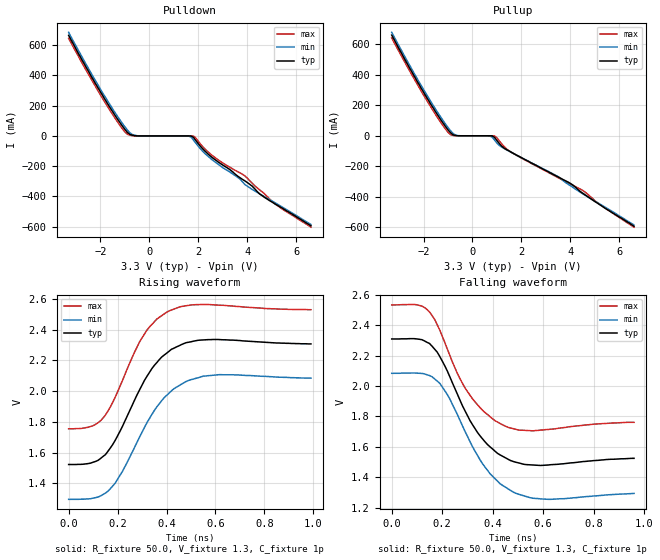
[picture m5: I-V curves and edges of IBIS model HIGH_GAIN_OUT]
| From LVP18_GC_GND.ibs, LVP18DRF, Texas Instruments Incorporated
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|   Driver Output Model
[Model]   HIGH_GAIN_OUT
Model_type   Output_ECL
| Signals   Y,Z
Vmeas = 2.0V   |Reference voltage for timing measurements
Cref = 0pF   |Timing specification test load capacitance value
Rref = 50
|Note: 50 Ohm load; single ended configuration
| variable   typ   min   max
C_comp   0.8pF   0.6pF   0.9pF
|   typ   min   max
[Temperature Range]   25   -40   85
[Voltage range]   3.3V   3.0V   3.6V
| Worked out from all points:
|   rising waveform, R_fixture 50.0, V_fixture 1.3, C_fixture 1p: 20-80 % time 152ps typ, 164ps min, 137ps max; typ from 1.52 V to 2.31 V
|   falling waveform, R_fixture 50.0, V_fixture 1.3, C_fixture 1p: 20-80 % time 142ps typ, 150ps min, 133ps max; typ from 2.31 V to 1.52 V
[Pulldown]
|Voltage I(typ)   I(min)   I(max)
| Note that the[Pulldown]voltage table for (P)ECL is referenced
| to Vcc and is calculated using Vtable=Vcc - Vmeasured.
-3.3V     665mA      685mA      645mA
-1.6V     185mA      204mA      166mA
-1V       43mA       59.7mA     26.4mA
-800mV    10.5mA     21.4mA     5.1mA
-400mV    4.63uA     184uA      6.49nA
1.6V      -13.8uA    -610uA     -49.5nA
1.8V      -9.83mA    -27mA      -827uA
2.6V      -147mA     -162mA     -133mA
3.7V      -276mA     -285mA     -244mA
3.9V      -297mA     -321mA     -264mA
5.1V      -446mA     -439mA     -446mA
6.6V      -594mA     -585mA     -603mA
[Pullup]
|Voltage   I(typ)   I(min)   I(max)
| Note that the[Pullup]voltage table is referenced to Vcc
| and is calculated using Vtable=Vcc - Vmeasured.
-3.3V     660mA      678mA      641mA
-1.6V     181mA      198mA      162mA
-1V       38.9mA     54.4mA     22.9mA
-800mV    6.8mA      16.6mA     2.2mA
-600mV    174uA      993uA      1.73uA
700mV     -17.7uA    -731uA     -46.4nA
900mV     -10.8mA    -27.6mA    -775uA
1.2V      -69.4mA    -74.7mA    -54.2mA
1.5V      -100mA     -101mA     -99.8mA
3.5V      -270mA     -268mA     -275mA
4.5V      -376mA     -380mA     -358mA
6.6V      -593mA     -585mA     -599mA
[Ramp]
|   typ   min   max
dV/dt_r   0.472/150ps   0.476/160ps   0.465/140ps
dV/dt_f   0.470/140ps   0.474/150ps   0.463/130ps
R_load = 50ohm  |Note: The measurement is with 50ohm to Vtt.
[Rising Waveform]
R_fixture = 50.0
V_fixture = 1.3
V_fixture_min = 1.0
V_fixture_max = 1.6
C_fixture = 1p
L_fixture = 0n
|   V(typ)  V(min)  V(max)
0s        1.522V     1.295V     1.755V
100ps     1.537V     1.303V     1.775V
160ps     1.607V     1.347V     1.869V
220ps     1.771V     1.478V     2.07V
290ps     2.009V     1.702V     2.322V
350ps     2.168V     1.874V     2.452V
410ps     2.26V      1.987V     2.523V
480ps     2.316V     2.063V     2.557V
550ps     2.334V     2.098V     2.565V
990ps     2.308V     2.085V     2.531V
[Falling Waveform]
R_fixture = 50.0
V_fixture = 1.3
V_fixture_min = 1.0
V_fixture_max = 1.6
C_fixture = 1p
L_fixture = 0n
|   V(typ)  V(min)  V(max)
0s        2.31V      2.084V     2.534V
120ps     2.305V     2.083V     2.526V
150ps     2.28V      2.069V     2.487V
190ps     2.196V     2.019V     2.37V
290ps     1.838V     1.703V     1.989V
360ps     1.652V     1.488V     1.84V
440ps     1.537V     1.345V     1.744V
500ps     1.495V     1.289V     1.711V
610ps     1.479V     1.255V     1.713V
960ps     1.524V     1.293V     1.761V
